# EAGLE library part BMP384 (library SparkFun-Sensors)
Bosch BMP384 Pressure Sensor Senses pressure from 300 hPa to 1250 hPa, sends data out over I2C or SPI

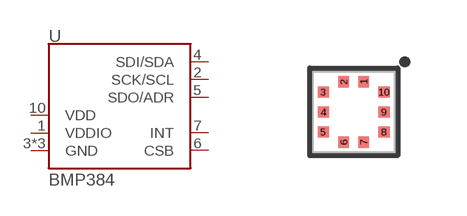
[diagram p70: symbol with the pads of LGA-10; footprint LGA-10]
Designator prefix U

## BMP384 (PROD_ID: IC-16677)  [LGA-10]
1  VDDIO  pwr
2  SCK/SCL
3  GND  pwr
4  SDI/SDA
5  SDO/ADR
6  CSB  in
7  INT  out
8  GND  pwr
9  GND  pwr
10  VDD  pwr

## Footprint LGA-10 (pad centres in mm)
LGA10 Specifications: Pin count: 10 Pin pitch: .5mm Area: 2.0 x 2.0 mm Datasheet referenced for footprint
smd 0.27 x 0.285: 1 0.25,0.757; 2 -0.25,0.757; 6 -0.25,-0.757; 7 0.25,-0.757
smd 0.285 x 0.27: 3 -0.757,0.5; 4 -0.757,0; 5 -0.757,-0.5; 8 0.757,-0.5; 9 0.757,0; 10 0.757,0.5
